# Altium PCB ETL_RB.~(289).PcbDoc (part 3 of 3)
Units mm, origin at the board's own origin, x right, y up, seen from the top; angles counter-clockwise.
Board outline 130.3 x 56.5 mm, 8 copper layers (Top Layer, plane 1, M1, plane 2, plane 3, M2, plane 4, Bottom Layer), stack 0.972 mm thick; 198 components, 185 nets, 1814 pads, 863 vias.
Unrouted connection lines stored in the file: 412.

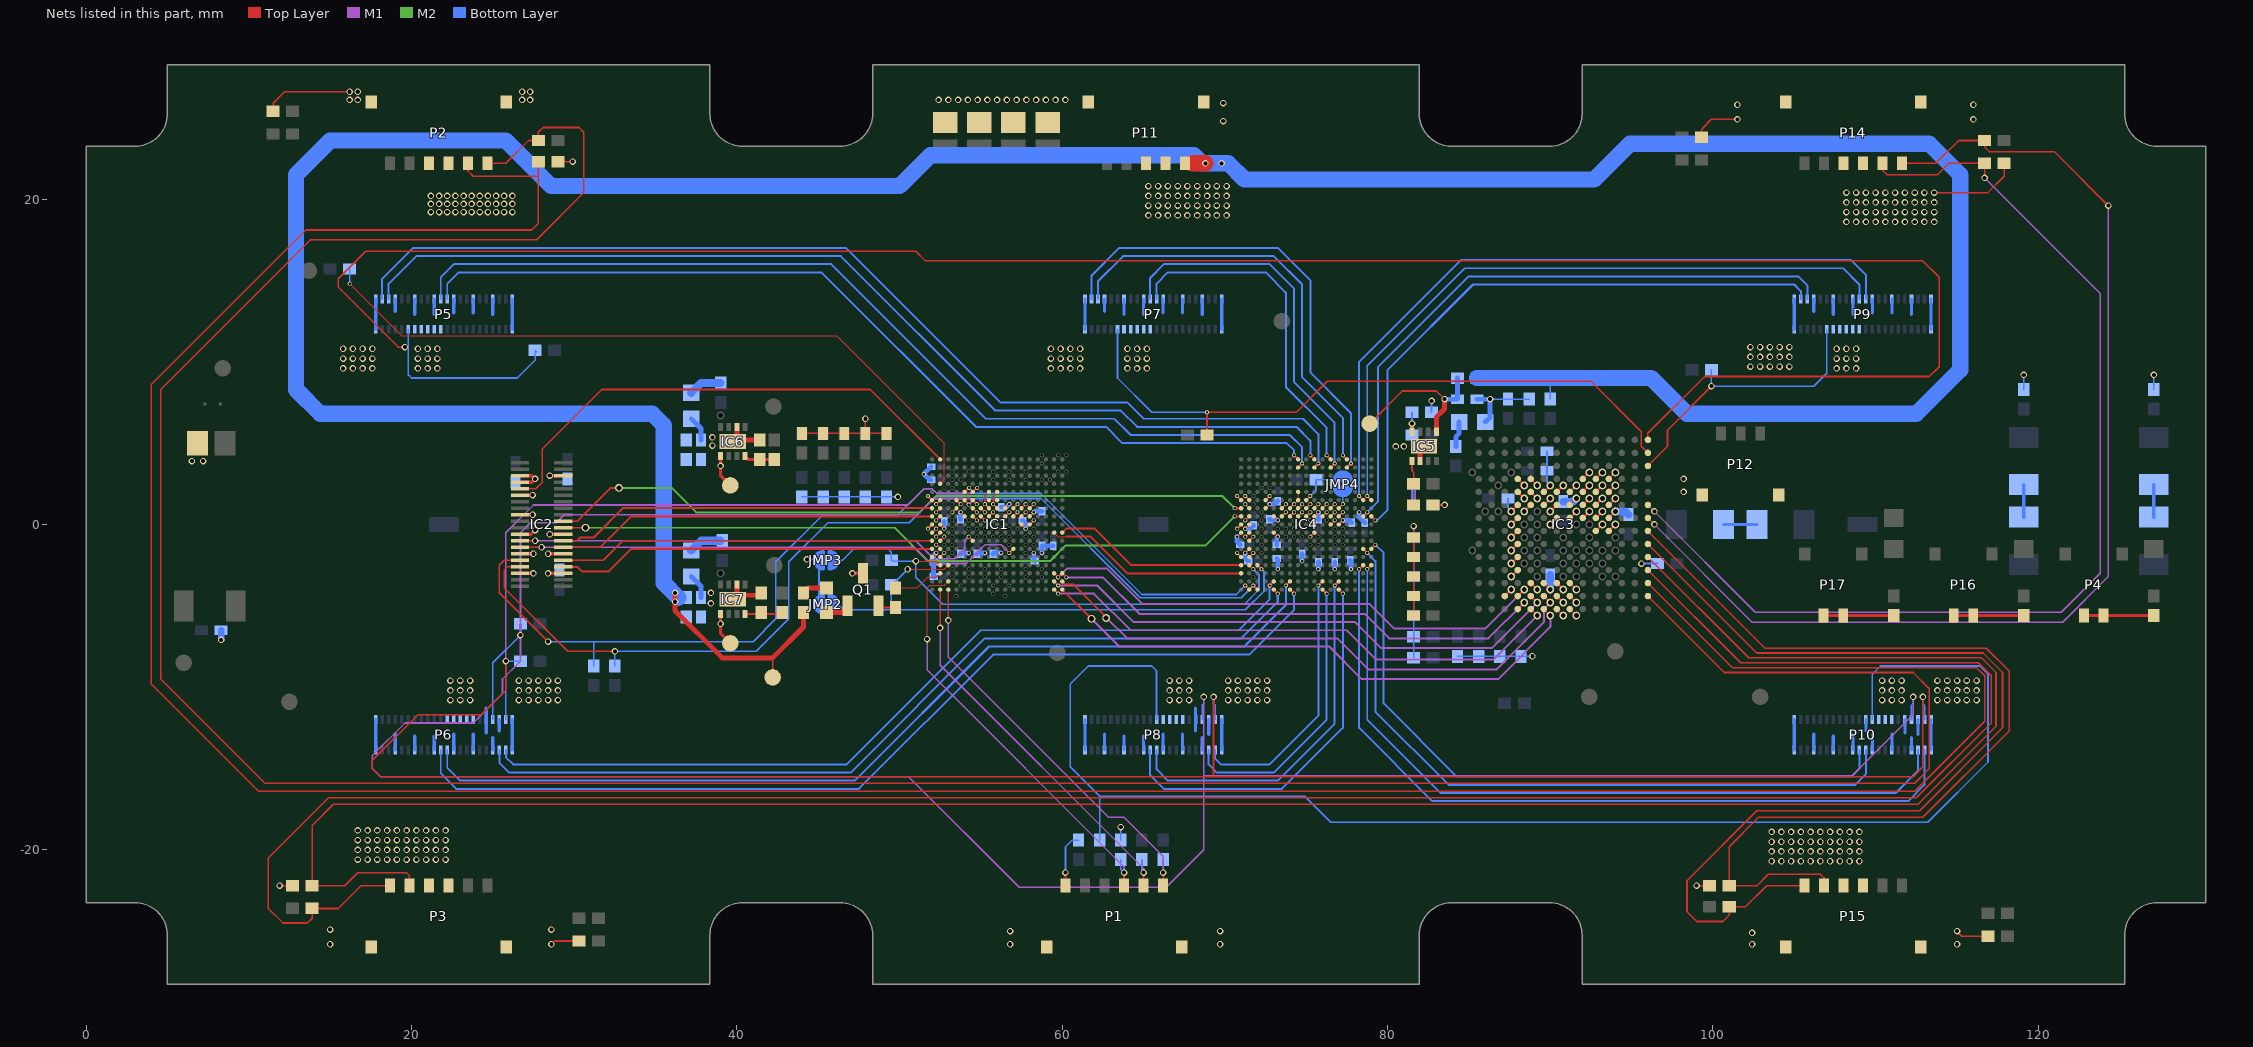
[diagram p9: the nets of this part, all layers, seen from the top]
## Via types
v1: diameter 0.4, hole 0.25, Top Layer to Bottom Layer, 863 vias

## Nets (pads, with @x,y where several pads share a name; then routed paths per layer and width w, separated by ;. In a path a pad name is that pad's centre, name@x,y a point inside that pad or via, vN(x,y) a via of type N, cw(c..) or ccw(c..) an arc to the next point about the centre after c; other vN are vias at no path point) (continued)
GND: C105.2 C106.2 C107.2 C108.2 C109.2 C111.2 C112.2 C113.2 C114.2 C115.2 C116.2 C117.2 C118.2 C119.2 C120.2 C121.2 C122.2 C123.2 C124.2 C125.2 C126.2 C127.2 C128.2 C129.2 C130.2 C131.2 C132.2 C133.2 C134.2 C135.2 C136.2 C138.2 C139.2 C140.2 C141.2 C142.2 C150.2 C151.2 C152.2 C153.2 C154.2 C155.2 C158.2 C159.2 C160.2 C162.2 C163.2 C164.2 C165.2 C166.2 C167.2 C168.2 C169.2 C201.1 C202.1 C203.1 C204.1 C205.1 C206.1 C207.1 C208.1 C209.1 C210.1 C211.1 C212.1 C213.1 C214.1 IC1.E8 IC1.E9 IC1.F1 IC1.F2 IC1.F4 IC1.F8 IC1.F9 IC1.G2 IC1.G4 IC1.G6 IC1.G7 IC1.G8 IC1.G9 IC1.G10 IC1.G11 IC1.G12 IC1.G13 IC1.H2 IC1.H5 IC1.H6 IC1.H7 IC1.H8 IC1.H9 IC1.H10 IC1.H11 IC1.H12 IC1.H13 IC1.J1 IC1.J2 IC1.J12 IC1.J13 IC1.K1 IC1.K2 IC1.L2 IC1.M2 IC1.N1 IC1.N2 IC2.5 IC2.6 IC2.11 IC2.12 IC2.17 IC2.18 IC2.24 IC2.30 IC2.34 IC2.35 IC2.36 IC3.D4 IC3.D5 IC3.D6 IC3.D7 IC3.D8 IC3.E4 IC3.E5 IC3.E6 IC3.E7 IC3.E8 IC3.F4 IC3.F5 IC3.F6 IC3.F7 IC3.G5 IC3.G6 IC3.G7 IC3.G12 IC3.G13 IC3.G14 IC3.H5 IC3.H6 IC3.H7 IC3.H12 IC3.H13 IC3.H14 IC3.J5 IC3.J6 IC3.J12 IC3.K4 IC3.K5 IC3.K6 IC3.K12 IC3.L4 IC3.L5 IC3.L6 IC3.L7 IC3.L8 IC3.L9 IC3.L10 IC3.L11 IC3.M13 IC4.E8 IC4.F1 IC4.F2 IC4.F4 IC4.F8 IC4.G2 IC4.G4 IC4.G6 IC4.G7 IC4.G8 IC4.G9 IC4.G10 IC4.G11 IC4.G12 IC4.G13 IC4.H2 IC4.H5 IC4.H6 IC4.H7 IC4.H8 IC4.H9 IC4.H10 IC4.H11 IC4.H12 IC4.H13 IC4.J1 IC4.J2 IC4.J10 IC4.J12 IC4.J13 IC4.K1 IC4.K2 IC4.K5 IC4.K10 IC4.L2 IC4.M2 IC4.N1 IC4.N2 IC5.6 IC5.9 IC6.6 IC6.9 IC7.6 IC7.9 JMP2.1 JMP3.1 JMP4.1 P1.6 P1.7 P1.8 P2.3 P2.4 P2.7 P2.8 P3.3 P3.4 P3.7 P3.8 P5.11 P5.12 P5.13 P5.14 P5.15 P5.23 P5.26 P5.29 P5.32 P5.35 P5.38 P5.41 P5.42 P5.43 P5.44 P6.11 P6.12 P6.13 P6.14 P6.15 P6.17 P6.19 P6.23 P6.26 P6.29 P6.32 P6.35 P6.38 P6.41 P6.42 P6.43 P6.44 P7.11 P7.12 P7.13 P7.14 P7.15 P7.23 P7.26 P7.29 P7.32 P7.35 P7.38 P7.41 P7.42 P7.43 P7.44 P8.12 P8.13 P8.14 P8.15 P8.17 P8.19 P8.23 P8.26 P8.29 P8.32 P8.35 P8.38 P8.41 P8.42 P8.43 P8.44 P9.11 P9.12 P9.13 P9.14 P9.15 P9.23 P9.26 P9.29 P9.32 P9.35 P9.38 P9.41 P9.42 P9.43 P9.44 P10.11 P10.13 P10.14 P10.15 P10.17 P10.19 P10.23 P10.26 P10.29 P10.32 P10.35 P10.38 P10.41 P10.42 P10.43 P10.44 P11.3 P11.4 P11.6 P11.7 P12.4 P12.5 P14.3 P14.4 P14.7 P14.8 P15.3 P15.4 P15.7 P15.8 pad.1@51.5,3.1 pad.1@51.75,1.75 pad.1@51.75,-0.25 pad.1@52.25,0.25 pad.1@52.25,0.75 pad.1@52.25,1.25 pad.1@52.25,-0.25 pad.1@52.25,-0.75 pad.1@52.25,-1.25 pad.1@52.25,-1.75 pad.1@52.75,-0.25 pad.1@52.75,-0.75 pad.1@52.75,-1.75 pad.1@53.25,0.75 pad.1@53.75,0.75 pad.1@53.75,1.25 pad.1@54.25,-1.75 pad.1@54.75,0.25 pad.1@54.75,0.75 pad.1@55.25,0.25 pad.1@55.25,0.75 pad.1@55.25,1.25 pad.1@55.25,-1.75 pad.1@55.75,0.25 pad.1@55.75,0.75 pad.1@55.75,1.25 pad.1@56.25,-1.75 pad.1@56.75,0.75 pad.1@56.75,1.25 pad.1@57.25,0.75 pad.1@57.25,1.25 pad.1@57.75,0.75 pad.1@57.75,1.25 pad.1@57.75,-0.25 pad.1@58.25,0.25 pad.1@58.25,0.75 pad.1@58.25,1.25 pad.1@58.25,-1.75 pad.1@58.75,-1.75 pad.1@70.75,1.75 pad.1@70.75,-0.25 pad.1@70.75,-0.75 pad.1@70.75,-1.75 pad.1@71.25,0.25 pad.1@71.25,1.25 pad.1@71.25,1.75 pad.1@71.25,-0.25 pad.1@71.25,-0.75 pad.1@71.25,-1.75 pad.1@71.75,-0.75 pad.1@71.75,-1.75 pad.1@72.75,1.25 pad.1@72.75,1.75 pad.1@73.25,0.25 pad.1@73.25,-0.75 pad.1@73.25,-2.75 pad.1@73.75,0.75 pad.1@73.75,1.25 pad.1@74.25,0.75 pad.1@74.25,1.25 pad.1@74.75,0.75 pad.1@74.75,1.25 pad.1@74.75,-2.25 pad.1@75.25,0.25 pad.1@75.25,0.75 pad.1@75.25,1.25 pad.1@75.25,-0.75 pad.1@75.75,0.75 pad.1@75.75,1.25 pad.1@75.75,-2.75 pad.1@76.25,0.75 pad.1@76.25,1.25 pad.1@76.75,0.25 pad.1@76.75,0.75 pad.1@76.75,1.25 pad.1@76.75,-2.75 pad.1@77.25,0.25 pad.1@77.25,0.75 pad.1@77.25,1.25 pad.1@77.75,-2.75 pad.1@78.25,0.75 pad.1@87.6,0 pad.1@87.6,0.8 pad.1@87.6,-0.8 pad.1@87.6,-1.6 pad.1@87.6,-2.4 pad.1@87.6,-3.2 pad.1@87.6,-4 pad.1@88.4,0.8 pad.1@88.4,1.6 pad.1@88.4,2.4 pad.1@89.2,1.6 pad.1@89.2,2.4 pad.1@89.2,-4 pad.1@90,0 pad.1@90,0.8 pad.1@90,1.6 pad.1@90,2.4 pad.1@90,-4 pad.1@90.8,2.4 pad.1@90.8,-4 pad.1@90.8,-4.8 pad.1@90.8,-5.6 pad.1@91.6,0.8 pad.1@91.6,1.6 pad.1@91.6,2.4 pad.1@91.6,-4 pad.1@91.6,-4.8 pad.1@91.6,-5.6 pad.1@92.4,0.8 pad.1@92.4,1.6 pad.1@92.4,2.4 pad.1@92.4,3.2 pad.1@93.2,0 pad.1@93.2,0.8 pad.1@93.2,1.6 pad.1@93.2,2.4 pad.1@93.2,3.2 pad.1@94,0 pad.1@94,0.8 pad.1@94,1.6 pad.1@94,2.4 pad.1@94,3.2 Q1.3 R112.2 R115.2 R118.1 R120.1 R122.1 R123.2 R126.2 R132.2 R134.1 R136.1 R143.1 R203.1 R205.1 R207.1 R209.1 R211.1 R213.1 R215.1 R217.1 R219.1 R221.1 R223.1 R225.1 R227.1 R229.1 R233.2 R234.2 R235.2 R236.2 | length 222
  Top Layer w0.076: pad.1@55.25,1.25 55.25,1.5 ; IC1.F8@55.5,1.5 55.25,1.5 ; IC1.E8@55.5,2 55.25,1.75 55.25,1.5 ; pad.1@55.75,1.25 55.75,1.5 ; IC1.F9@56,1.5 55.75,1.5 ; IC1.E9@56,2 55.75,1.75 55.75,1.5 ; pad.1@74.25,1.25 IC4.F8@74.5,1.5 IC4.E8@74.5,2
  Top Layer w0.102: R215.1@11.5,25.4 11.5,25.9 12.2,26.6 v1(16.2,26.6) ; v1(11.9,-22.2) R234.2@12.7,-22.2 ; v1(28.6,-25.8) 28.8,-25.6 R217.1@30.3,-25.6 ; R233.2@29,22.3 v1(29.9,22.3) ; C151.2@44,5.6 C150.2@45.3,5.6 C142.2@46.6,5.6 C109.2@47.9,5.6 ; v1(47.9,6.5) C109.2@47.9,5.6 ; C141.2@49.2,5.6 C109.2@47.9,5.6 ; P1.6@60.2,-22.2 v1(60.2,-21.4) ; C201.1@81.6,-5.6 C203.1@81.6,-4.4 C205.1@81.6,-3.2 C207.1@81.6,-2 C210.1@81.6,-0.8 v1(81.6,-0.1) ; R112.2@82.8,1.2 v1(83.5,1.2) ; v1(99,-22.2) R236.2@99.8,-22.2 ; R219.1@99.3,23.8 99.3,24.3 99.9,24.9 v1(101.5,24.9) ; v1(113.6,20.4) 116.9,20.4 117.9,21.4 R235.2@117.9,22.2 ; v1(115,-25) 115.3,-25.3 R221.1@116.9,-25.3
  Top Layer w0.13: pad.1@51.75,-0.25 IC1.J1@52,0 ; pad.1@51.75,1.75 IC1.F1@52,1.5 ; IC1.N1@52,-2 pad.1@52.25,-1.75 ; IC1.K1@52,-0.5 pad.1@52.25,-0.25 ; pad.1@52.25,-1.25 IC1.M2@52.5,-1.5 ; pad.1@52.25,-0.75 IC1.K2@52.5,-0.5 ; pad.1@52.25,0.25 IC1.H2@52.5,0.5 ; pad.1@52.25,0.75 IC1.G2@52.5,1 ; pad.1@52.25,1.25 IC1.F2@52.5,1.5 ; IC1.N2@52.5,-2 pad.1@52.75,-1.75 ; IC1.L2@52.5,-1 pad.1@52.75,-0.75 ; IC1.J2@52.5,0 pad.1@52.75,-0.25 ; pad.1@53.25,0.75 IC1.G4@53.5,1 ; IC1.F4@53.5,1.5 pad.1@53.75,1.25 ; pad.1@53.75,0.75 IC1.H5@54,0.5 ; IC1.H6@54.5,0.5 pad.1@54.75,0.25 ; IC1.G6@54.5,1 pad.1@54.75,0.75 ; IC1.H7@55,0.5 pad.1@55.25,0.25 ; IC1.G7@55,1 pad.1@55.25,0.75 ; pad.1@55.25,1.25 IC1.G8@55.5,1 ; IC1.H8@55.5,0.5 pad.1@55.75,0.75 ; pad.1@55.75,0.25 IC1.H9@56,0.5 ; pad.1@55.75,1.25 IC1.G9@56,1 ; IC1.H10@56.5,0.5 pad.1@56.75,0.75 ; IC1.G10@56.5,1 pad.1@56.75,1.25 ; IC1.H11@57,0.5 pad.1@57.25,0.75 ; IC1.G11@57,1 pad.1@57.25,1.25 ; IC1.J12@57.5,0 pad.1@57.75,-0.25 ; IC1.H12@57.5,0.5 pad.1@57.75,0.75 ; IC1.G12@57.5,1 pad.1@57.75,1.25 ; IC1.J13@58,0 pad.1@58.25,0.25 ; IC1.H13@58,0.5 pad.1@58.25,0.75 ; IC1.G13@58,1 pad.1@58.25,1.25 ; pad.1@70.75,-1.75 IC4.N1@71,-2 ; pad.1@70.75,-0.75 IC4.K1@71,-0.5 ; pad.1@70.75,-0.25 IC4.J1@71,0 ; pad.1@70.75,1.75 IC4.F1@71,1.5 ; pad.1@71.25,-1.75 IC4.M2@71.5,-1.5 ; pad.1@71.25,-0.75 IC4.K2@71.5,-0.5 ; pad.1@71.25,-0.25 IC4.J2@71.5,0 ; pad.1@71.25,0.25 IC4.H2@71.5,0.5 ; pad.1@71.25,1.25 IC4.G2@71.5,1 ; pad.1@71.25,1.75 IC4.F2@71.5,1.5 ; IC4.N2@71.5,-2 pad.1@71.75,-1.75 ; IC4.L2@71.5,-1 pad.1@71.75,-0.75 ; IC4.G4@72.5,1 pad.1@72.75,1.25 ; IC4.F4@72.5,1.5 pad.1@72.75,1.75 ; IC4.K5@73,-0.5 pad.1@73.25,-0.75 ; IC4.H5@73,0.5 pad.1@73.25,0.25 ; IC4.H6@73.5,0.5 pad.1@73.75,0.75 ; IC4.G6@73.5,1 pad.1@73.75,1.25 ; IC4.H7@74,0.5 pad.1@74.25,0.75 ; IC4.G7@74,1 pad.1@74.25,1.25 ; IC4.H8@74.5,0.5 pad.1@74.75,0.75 ; IC4.G8@74.5,1 pad.1@74.75,1.25 ; IC4.H9@75,0.5 pad.1@75.25,0.75 ; IC4.G9@75,1 pad.1@75.25,1.25 ; pad.1@75.25,-0.75 IC4.K10@75.5,-0.5 ; pad.1@75.25,0.25 IC4.J10@75.5,0 ; IC4.H10@75.5,0.5 pad.1@75.75,0.75 ; IC4.G10@75.5,1 pad.1@75.75,1.25 ; IC4.H11@76,0.5 pad.1@76.25,0.75 ; IC4.G11@76,1 pad.1@76.25,1.25 ; IC4.J12@76.5,0 pad.1@76.75,0.25 ; IC4.H12@76.5,0.5 pad.1@76.75,0.75 ; IC4.G12@76.5,1 pad.1@76.75,1.25 ; IC4.J13@77,0 pad.1@77.25,0.25 ; IC4.H13@77,0.5 pad.1@77.25,0.75 ; IC4.G13@77,1 pad.1@77.25,1.25 ; IC3.M13@87.2,-4.4 pad.1@87.6,-4 ; pad.1@87.6,-3.2 IC3.L11@88,-2.8 ; pad.1@87.6,-2.4 IC3.L10@88,-2 ; pad.1@87.6,-1.6 IC3.L9@88,-1.2 ; pad.1@87.6,-0.8 IC3.L8@88,-0.4 ; pad.1@87.6,0 IC3.L7@88,0.4 ; pad.1@87.6,0.8 IC3.L6@88,1.2 ; IC3.L5@88,2 pad.1@88.4,1.6 ; IC3.L4@88,2.8 pad.1@88.4,2.4 ; pad.1@88.4,0.8 IC3.K6@88.8,1.2 ; IC3.K12@88.8,-3.6 pad.1@89.2,-4 ; IC3.K5@88.8,2 pad.1@89.2,1.6 ; IC3.K4@88.8,2.8 pad.1@89.2,2.4 ; IC3.J12@89.6,-3.6 pad.1@90,-4 ; IC3.J6@89.6,1.2 pad.1@90,1.6 ; IC3.J5@89.6,2 pad.1@90,2.4 ; pad.1@90,0 IC3.H7@90.4,0.4 ; pad.1@90,0.8 IC3.H6@90.4,1.2 ; IC3.H14@90.4,-5.2 pad.1@90.8,-5.6 ; IC3.H13@90.4,-4.4 pad.1@90.8,-4.8 ; IC3.H12@90.4,-3.6 pad.1@90.8,-4 ; IC3.H5@90.4,2 pad.1@90.8,2.4 ; IC3.G14@91.2,-5.2 pad.1@91.6,-5.6 ; IC3.G13@91.2,-4.4 pad.1@91.6,-4.8 ; IC3.G12@91.2,-3.6 pad.1@91.6,-4 ; IC3.G7@91.2,0.4 pad.1@91.6,0.8 ; IC3.G6@91.2,1.2 pad.1@91.6,1.6 ; IC3.G5@91.2,2 pad.1@91.6,2.4 ; IC3.F7@92,0.4 pad.1@92.4,0.8 ; IC3.F6@92,1.2 pad.1@92.4,1.6 ; IC3.F5@92,2 pad.1@92.4,2.4 ; IC3.F4@92,2.8 pad.1@92.4,3.2 ; IC3.E8@92.8,-0.4 pad.1@93.2,0 ; IC3.E7@92.8,0.4 pad.1@93.2,0.8 ; IC3.E6@92.8,1.2 pad.1@93.2,1.6 ; IC3.E5@92.8,2 pad.1@93.2,2.4 ; IC3.E4@92.8,2.8 pad.1@93.2,3.2 ; IC3.D8@93.6,-0.4 pad.1@94,0 ; IC3.D7@93.6,0.4 pad.1@94,0.8 ; IC3.D6@93.6,1.2 pad.1@94,1.6 ; IC3.D5@93.6,2 pad.1@94,2.4 ; IC3.D4@93.6,2.8 pad.1@94,3.2
  Top Layer w0.2: IC2.6@26.67,-3 v1(27.5,-3) ; IC2.12@26.67,-1.8 v1(27.5,-1.8) ; IC2.18@26.67,-0.6 27.35,-0.6 v1(27.6,-0.35) ; IC2.24@26.67,0.6 v1(27.45,0.6) ; IC2.30@26.67,1.8 v1(27.45,1.8) ; IC2.34@26.67,2.6 27.4,2.6 v1(27.6,2.8) 27.4,3 IC2.36@26.67,3 ; v1(28.4,-3) IC2.5@29.33,-3 ; v1(28.4,-1.8) IC2.11@29.33,-1.8 ; v1(28.5,-0.6) IC2.17@29.33,-0.6 ; v1(28.5,3) IC2.35@29.33,3 ; v1(47.1,-3) Q1.3@47.75,-3
  Top Layer w0.3: IC7.9@39.75,-4.6 IC7.9@40,-4.35 ; IC7.6@40,-3.7 IC7.9@40,-4.35 ; IC6.6@40,6 40,5.35 39.875,5.225 39.9,5.2 R115.2@41.4,5.2 ; R123.2@41.5,-4.2 41.55,-4.2 41.4,-4.35 IC7.9@40,-4.35 ; IC5.6@82,3.9 82,4.55 IC5.9@82.25,4.8
  Bottom Layer w0.102: R122.1@44,1.7 R120.1@45.3,1.7 R136.1@46.6,1.7 R118.1@47.9,1.7 R134.1@49.2,1.7 v1(49.9,1.7) ; v1(44.3,-2.15) 44.803,-2.15 44.95,-2.15 JMP3.1@45,-2.2 ; 45.05,-4.467 45.05,-2.633 ; v1(60.2,-21.4) 60.2,-19.8 60.6,-19.4 R132.2@61,-19.4 ; R143.1@63.6,-19.4 v1(63.6,-18.6) ; pad.1@77.25,1.25 77.25,1.8 JMP4.1@77.25,2 ; R203.1@81.6,-8.2 R205.1@81.6,-6.9 C202.1@81.6,-5.6 C204.1@81.6,-4.4 C206.1@81.6,-3.2 C208.1@81.6,-2 C209.1@81.6,-0.8 81.6,-0.2 v1(81.6,-0.1) ; R126.2@82.7,6.9 v1(82.7,7.6) ; C155.2@82.8,1.2 v1(83.5,1.2) ; R207.1@84.3,-8.1 R209.1@85.6,-8.1 R211.1@86.9,-8.1 R213.1@88.2,-8.1 v1(88.9,-8.1) ; v1(86.3,7.7) C214.1@87.4,7.7 R229.1@88.7,7.7 ; C211.1@87.4,1.6 87.4,1 pad.1@87.6,0.8 ; C213.1@89.8,4.5 C212.1@89.8,3.3 89.8,2.6 pad.1@90,2.4 ; v1(95.6,-2.4) R227.1@96.6,-2.4 ; R225.1@119.1,8.3 v1(119.1,9.2) ; R223.1@127.1,8.3 v1(127.1,9.2)
  Bottom Layer w0.2: P6.44@17.8,-13.85 P6.41@17.8,-12 ; P5.42@17.8,12 P5.43@17.8,13.85 ; P6.38@19,-13.85 19,-12.9 ; 19,13.1 P5.23@19,13.85 ; P6.35@20.2,-13.85 20.2,-13 ; 20.2,12.9 P5.26@20.2,13.85 ; P6.32@21.4,-13.85 21.4,-13 ; 21.4,12.9 P5.29@21.4,13.85 ; P6.29@22.6,-13.85 22.6,-12.9 ; 22.6,13 P5.32@22.6,13.85 ; P6.26@23.8,-13.85 23.8,-12.9 ; 23.8,13 P5.35@23.8,13.85 ; 24.6,-12.8 P6.17@24.6,-12 24.6,-11.3 ; P6.23@25,-13.85 25,-13.1 ; 25,12.9 P5.38@25,13.85 ; 25.4,-12.7 P6.19@25.4,-12 ; P6.43@26.2,-13.85 P6.42@26.2,-12 ; P5.41@26.2,12 P5.44@26.2,13.85 ; P8.44@61.4,-13.85 P8.41@61.4,-12 ; P7.42@61.4,12 P7.43@61.4,13.85 ; P8.38@62.6,-13.85 62.6,-12.9 ; 62.6,13.1 P7.23@62.6,13.85 ; P8.35@63.8,-13.85 63.8,-13 ; 63.8,12.9 P7.26@63.8,13.85 ; P8.32@65,-13.85 65,-13 ; 65,12.9 P7.29@65,13.85 ; P8.29@66.2,-13.85 66.2,-12.9 ; 66.2,13 P7.32@66.2,13.85 ; P8.26@67.4,-13.85 67.4,-12.9 ; 67.4,13 P7.35@67.4,13.85 ; 68.2,-12.7 P8.17@68.2,-12 68.2,-11.3 ; P8.23@68.6,-13.85 68.6,-13.1 ; 68.6,12.9 P7.38@68.6,13.85 ; 69,-12.9 P8.19@69,-12 ; P8.43@69.8,-13.85 P8.42@69.8,-12 ; P7.41@69.8,12 P7.44@69.8,13.85 ; P10.44@105,-13.85 P10.41@105,-12 ; P9.42@105,12 P9.43@105,13.85 ; P10.38@106.2,-13.85 106.2,-12.9 ; 106.2,13.1 P9.23@106.2,13.85 ; P10.35@107.4,-13.85 107.4,-13 ; 107.4,12.9 P9.26@107.4,13.85 ; P10.32@108.6,-13.85 108.6,-13 ; 108.6,12.9 P9.29@108.6,13.85 ; 109.4,-12.7 P10.11@109.4,-12 ; P10.29@109.8,-13.85 109.8,-12.9 ; 109.8,13 P9.32@109.8,13.85 ; P10.26@111,-13.85 111,-12.9 ; 111,13 P9.35@111,13.85 ; 111.8,-12.8 P10.17@111.8,-12 ; P10.23@112.2,-13.85 112.2,-13.1 ; 112.2,12.9 P9.38@112.2,13.85 ; 112.6,-12.9 P10.19@112.6,-12 ; P10.43@113.4,-13.85 P10.42@113.4,-12 ; P9.41@113.4,12 P9.44@113.4,13.85
  Bottom Layer w0.3: C169.2@37.2,-3.2 37.8,-3.8 C152.2@37.8,-4.5 ; C108.2@37.2,6.5 37.8,5.9 C106.2@37.8,5.2 ; C119.2@51.94,2.75 51.85,2.75 pad.1@51.5,3.1 51.5,3.11 C118.2@51.94,3.55 ; C121.2@52.09,-3.2 52.174,-3.2 52.09,-3.116 C125.2@52.09,-2.3 52.09,-1.91 pad.1@52.25,-1.75 ; pad.1@52.75,-0.25 C116.2@52.75,0.19 ; C117.2@53.75,-1.81 53.81,-1.75 pad.1@54.25,-1.75 ; C126.2@53.75,0.31 pad.1@53.75,0.75 ; C114.2@54.75,-1.81 54.81,-1.75 pad.1@55.25,-1.75 ; C122.2@55.75,-1.81 55.81,-1.75 pad.1@56.25,-1.75 ; C120.2@56.25,1.06 56.56,1.06 pad.1@56.75,1.25 ; C136.2@57.56,0.25 57.75,0.06 pad.1@57.75,-0.25 ; pad.1@58.25,-1.75 58.25,-2.19 C123.2@58.31,-2.25 ; pad.1@58.25,0.75 58.31,0.81 C124.2@58.75,0.81 ; pad.1@58.75,-1.75 C115.2@58.75,-1.31 C113.2@59.45,-1.31 ; pad.1@70.75,-0.75 70.75,-1.06 C130.2@70.94,-1.25 ; pad.1@71.25,-1.75 71.25,-2.06 C132.2@71.44,-2.25 ; pad.1@71.25,-0.25 71.56,-0.25 C164.2@71.75,-0.06 ; C163.2@72.75,0.31 73.19,0.31 pad.1@73.25,0.25 ; pad.1@72.75,1.25 73.06,1.25 C167.2@73.25,1.44 ; C133.2@73.19,-2.1 73.25,-2.16 pad.1@73.25,-2.75 ; C168.2@73.19,-1.25 73.19,-0.81 pad.1@73.25,-0.75 ; pad.1@74.75,-2.25 C128.2@74.75,-1.81 ; pad.1@75.75,-2.75 C134.2@75.75,-2.31 ; C131.2@75.75,0.31 pad.1@75.75,0.75 ; pad.1@76.75,-2.75 C165.2@76.75,-2.31 ; pad.1@77.25,0.25 77.66,0.25 C166.2@77.8,0.11 ; C135.2@77.7,-2.21 77.75,-2.26 pad.1@77.75,-2.75 ; pad.1@78.25,0.75 78.25,0.46 C129.2@78.6,0.11 ; C105.2@85.5,7.7 v1(86.3,7.7) 86.3,6.6 C107.2@86,6.3
  Bottom Layer w0.4: v1(8.3,-7.1) C158.2@8.3,-6.5
  Bottom Layer w0.48: pad.1@90,-4 C138.2@90,-3.1 ; C140.2@90.8,1.4 91.4,1.4 pad.1@91.6,1.6 ; pad.1@94,0.8 94.6,0.8 C139.2@94.8,0.6
  other v1: 15,-25.8 56.8,-25.8 69.7,-25.8 102.4,-25.8 115,-25.8 102.4,-25.1 56.8,-25 69.7,-25 15,-24.9 28.6,-24.9 103.6,-20.7 104.2,-20.7 104.8,-20.7 105.4,-20.7 106,-20.7 106.6,-20.7 107.2,-20.7 107.8,-20.7 108.4,-20.7 109,-20.7 16.7,-20.6 17.3,-20.6 17.9,-20.6 18.5,-20.6 19.1,-20.6 19.7,-20.6 20.3,-20.6 20.9,-20.6 21.5,-20.6 22.1,-20.6 103.6,-20.1 104.2,-20.1 104.8,-20.1 105.4,-20.1 106,-20.1 106.6,-20.1 107.2,-20.1 107.8,-20.1 108.4,-20.1 109,-20.1 16.7,-20 17.3,-20 17.9,-20 18.5,-20 19.1,-20 19.7,-20 20.3,-20 20.9,-20 21.5,-20 22.1,-20 103.6,-19.5 104.2,-19.5 104.8,-19.5 105.4,-19.5 106,-19.5 106.6,-19.5 107.2,-19.5 107.8,-19.5 108.4,-19.5 109,-19.5 16.7,-19.4 17.3,-19.4 17.9,-19.4 18.5,-19.4 19.1,-19.4 19.7,-19.4 20.3,-19.4 20.9,-19.4 21.5,-19.4 22.1,-19.4 103.6,-18.9 104.2,-18.9 104.8,-18.9 105.4,-18.9 106,-18.9 106.6,-18.9 107.2,-18.9 107.8,-18.9 108.4,-18.9 109,-18.9 16.7,-18.8 17.3,-18.8 17.9,-18.8 18.5,-18.8 19.1,-18.8 19.7,-18.8 20.3,-18.8 20.9,-18.8 21.5,-18.8 22.1,-18.8 22.4,-10.8 23,-10.8 23.6,-10.8 26.6,-10.8 27.2,-10.8 27.8,-10.8 28.4,-10.8 29,-10.8 66.6,-10.8 67.2,-10.8 67.8,-10.8 70.2,-10.8 70.8,-10.8 71.4,-10.8 72,-10.8 72.6,-10.8 110.4,-10.8 111,-10.8 111.6,-10.8 113.8,-10.8 114.4,-10.8 115,-10.8 115.6,-10.8 116.2,-10.8 22.4,-10.2 23,-10.2 23.6,-10.2 26.6,-10.2 27.2,-10.2 27.8,-10.2 28.4,-10.2 29,-10.2 66.6,-10.2 67.2,-10.2 67.8,-10.2 70.2,-10.2 70.8,-10.2 71.4,-10.2 72,-10.2 72.6,-10.2 110.4,-10.2 111,-10.2 111.6,-10.2 113.8,-10.2 114.4,-10.2 115,-10.2 115.6,-10.2 116.2,-10.2 22.4,-9.6 23,-9.6 23.6,-9.6 26.6,-9.6 27.2,-9.6 27.8,-9.6 28.4,-9.6 29,-9.6 66.6,-9.6 67.2,-9.6 67.8,-9.6 70.2,-9.6 70.8,-9.6 71.4,-9.6 72,-9.6 72.6,-9.6 110.4,-9.6 111,-9.6 111.6,-9.6 113.8,-9.6 114.4,-9.6 115,-9.6 115.6,-9.6 116.2,-9.6 38.4,-4.85 38.4,-4.2 98.2,2 98.2,2.8 6.5,3.9 7.2,3.9 80.5,4.8 81,4.8 38.5,4.85 38.5,5.35 15.8,9.6 16.4,9.6 17,9.6 17.6,9.6 20.4,9.6 21,9.6 21.6,9.6 59.3,9.6 59.9,9.6 60.5,9.6 61.1,9.6 64,9.6 64.6,9.6 65.2,9.6 107.6,9.6 108.2,9.6 108.8,9.6 102.3,9.7 102.9,9.7 103.5,9.7 104.1,9.7 104.7,9.7 15.8,10.2 16.4,10.2 17,10.2 17.6,10.2 20.4,10.2 21,10.2 21.6,10.2 59.3,10.2 59.9,10.2 60.5,10.2 61.1,10.2 64,10.2 64.6,10.2 65.2,10.2 107.6,10.2 108.2,10.2 108.8,10.2 102.3,10.3 102.9,10.3 103.5,10.3 104.1,10.3 104.7,10.3 15.8,10.8 16.4,10.8 17,10.8 17.6,10.8 20.4,10.8 21,10.8 21.6,10.8 59.3,10.8 59.9,10.8 60.5,10.8 61.1,10.8 64,10.8 64.6,10.8 65.2,10.8 107.6,10.8 108.2,10.8 108.8,10.8 102.3,10.9 102.9,10.9 103.5,10.9 104.1,10.9 104.7,10.9 108.2,18.6 108.8,18.6 109.4,18.6 110,18.6 110.6,18.6 111.2,18.6 111.8,18.6 112.4,18.6 113,18.6 113.6,18.6 65.3,19 65.9,19 66.5,19 67.1,19 67.7,19 68.3,19 68.9,19 69.5,19 70.1,19 21.2,19.2 21.7,19.2 22.2,19.2 22.7,19.2 23.2,19.2 23.7,19.2 24.2,19.2 24.7,19.2 25.2,19.2 25.7,19.2 26.2,19.2 108.2,19.2 108.8,19.2 109.4,19.2 110,19.2 110.6,19.2 111.2,19.2 111.8,19.2 112.4,19.2 113,19.2 113.6,19.2 65.3,19.6 65.9,19.6 66.5,19.6 67.1,19.6 67.7,19.6 68.3,19.6 68.9,19.6 69.5,19.6 70.1,19.6 21.2,19.7 21.7,19.7 22.2,19.7 22.7,19.7 23.2,19.7 23.7,19.7 24.2,19.7 24.7,19.7 25.2,19.7 25.7,19.7 26.2,19.7 108.2,19.8 108.8,19.8 109.4,19.8 110,19.8 110.6,19.8 111.2,19.8 111.8,19.8 112.4,19.8 113,19.8 113.6,19.8 21.2,20.2 21.7,20.2 22.2,20.2 22.7,20.2 23.2,20.2 23.7,20.2 24.2,20.2 24.7,20.2 25.2,20.2 25.7,20.2 26.2,20.2 65.3,20.2 65.9,20.2 66.5,20.2 67.1,20.2 67.7,20.2 68.3,20.2 68.9,20.2 69.5,20.2 70.1,20.2 108.2,20.4 108.8,20.4 109.4,20.4 110,20.4 110.6,20.4 111.2,20.4 111.8,20.4 112.4,20.4 113,20.4 65.3,20.8 65.9,20.8 66.5,20.8 67.1,20.8 67.7,20.8 68.3,20.8 68.9,20.8 69.5,20.8 70.1,20.8 69.9,24.8 116,24.9 101.5,25.8 116,25.8 69.9,25.9 16.2,26.1 16.7,26.1 26.8,26.1 27.3,26.1 52.4,26.1 53,26.1 53.6,26.1 54.2,26.1 54.8,26.1 55.4,26.1 56,26.1 56.6,26.1 57.2,26.1 57.8,26.1 58.4,26.1 59,26.1 59.6,26.1 60.2,26.1 16.7,26.6 26.8,26.6 27.3,26.6
I_1V5: C105.1 IC5.1 R129.2 TP15.1 | length 9.9
  Top Layer w0.102: TP15.1@78.9,6.2 80.9,8.2 83,8.2 v1(83.5,7.7)
  Top Layer w0.3: IC5.1@83,5.7 83,6.6 83.5,7.1 v1(83.5,7.7)
  Bottom Layer w0.3: v1(83.5,7.7) C105.1@84.3,7.7 R129.2@84.3,9
I_2V5RX: C152.1 IC7.1 R131.2 TP16.1 | length 2
  Top Layer w0.2: IC7.1@39,-5.5 v1(39,-6.1) 39,-6.7 TP16.1@39.6,-7.3
I_2V5TX: C106.1 IC6.1 R130.2 TP17.1 | length 2
  Top Layer w0.2: IC6.1@39,4.2 v1(39,3.6) 39,3 TP17.1@39.6,2.4
IC1_SCL: IC1.U2 P1.2 R110.1 | length 24.2
  Top Layer w0.102: v1(52.5,-6.35) IC1.U2@52.5,-4 ; P1.2@65,-22.2 v1(65,-21.4)
  M1 w0.102: v1(52.5,-6.35) 52.5,-8.65 65,-21.15 v1(65,-21.4)
  Bottom Layer w0.102: R110.1@64.9,-20.6 64.9,-21.3 v1(65,-21.4)
IC1_SDA: IC1.U3 P1.1 R109.1 | length 25
  Top Layer w0.102: v1(53,-5.9) 53,-4.9 IC1.U3@53,-4 ; P1.1@66.2,-22.2 v1(66.2,-21.4)
  M1 w0.102: v1(53,-5.9) 53,-6.4 53,-8.15 62.85,-18 63.8,-18 66.2,-20.4 v1(66.2,-21.4)
  Bottom Layer w0.102: v1(66.2,-21.4) R109.1@66.2,-20.6
LD_DIS: IC1.L6 IC2.16 pad.1@54.25,-0.75 | length 29.2
  Top Layer w0.102: IC2.16@26.67,-1 v1(27.6,-1)
  Top Layer w0.13: pad.1@54.25,-0.75 IC1.L6@54.5,-1
  M1 w0.102: v1(27.6,-1) 51,-1 52.1,-2.1 53.4,-2.1 54,-1.5 54,-1 pad.1@54.25,-0.75
LD_RSTN: IC1.M11 IC2.14 pad.1@56.75,-1.75 | length 31.5
  Top Layer w0.102: IC2.14@26.67,-1.4 v1(28,-1.4)
  Top Layer w0.13: pad.1@56.75,-1.75 IC1.M11@57,-1.5
  M1 w0.102: v1(28,-1.4) 50.9,-1.4 51.9,-2.4 54.1,-2.4 55.25,-1.25 56.25,-1.25 pad.1@56.75,-1.75
LV_RB: P11.5 R129.1 R130.1 R131.1 R142.1 R228.2 TP5.1 | length 214
  Top Layer w0.102: TP5.1@42.2,-9.4 42.2,-8.2
  Top Layer w0.3: v1(36.2,-4.2) v1(36.2,-4.75) 36.2,-5.3 39.1,-8.2 42.2,-8.2 44.1,-6.3 R142.1@44.1,-5.4
  Top Layer w1: 68,22.2 v1(68.8,22.2)
  Bottom Layer w0.102: R228.2@90,7.7 90,9
  Bottom Layer w1: 36.4,-4.5 35.5,-3.6 35.5,6.1 34.8,6.8 14.4,6.8 12.9,8.3 12.9,21.5 15,23.6 25.8,23.6 28.6,20.8 50,20.8 51.9,22.7 68.1,22.7 68.6,22.2 v1(68.8,22.2) v1(69.8,22.2) 70.2,22.2 71.2,21.2 92.7,21.2 94.9,23.4 113.3,23.4 115.2,21.5 115.2,9.5 112.5,6.8 98.4,6.8 96.2,9 90,9 R129.1@85.5,9
M1SCL: IC1.E6 P6.20 P8.20 P10.20 pad.1@54.775,2.25 R103.1 | length 163.3
  Top Layer w0.102: v1(25.8,-8.4) 25.8,-10.2 24.3,-11.7 20.4,-11.7 17.6,-14.5 17.6,-15 18.1,-15.5 69.3,-15.5 ; v1(69.3,-10.6) 69.3,-15.5 ; v1(112.9,-10.6) 112.9,-14.9 112.3,-15.5 69.3,-15.5
  Top Layer w0.13: IC1.E6@54.5,2 54.75,2.25 pad.1@54.775,2.25
  M1 w0.102: v1(25.8,-8.4) 25.8,-0.5 27.5,1.2 50.5,1.2 51.5,2.2 52,2.2 52.3,1.9 54.425,1.9 pad.1@54.775,2.25
  Bottom Layer w0.1: v1(69.3,-10.6) 69.3,-11 69.4,-11.1 P8.20@69.4,-12 ; v1(112.9,-10.6) 112.9,-11 113,-11.1 P10.20@113,-12
  Bottom Layer w0.102: P6.20@25.8,-12 v1(25.8,-8.4) R103.1@26.7,-8.4
M1SDA: IC1.F6 P6.18 P8.18 P10.18 pad.1@54.75,1.25 R104.1 | length 170.4
  Top Layer w0.13: IC1.F6@54.5,1.5 pad.1@54.75,1.25
  M1 w0.1: 66.4,-22.3 68.7,-20 ; 108.55,-15.45 112.3,-11.7 v1(112.3,-10.6)
  M1 w0.102: pad.1@54.75,1.25 54.4,1.6 52.1,1.6 51.1,0.6 29.4,0.6 28.9,0.1 27.3,0.1 26.7,-0.5 v1(26.7,-6.8) 26.7,-8.4 25.6,-9.5 25.6,-10.4 23.8,-12.2 19.6,-12.2 17.6,-14.2 17.6,-15 18.1,-15.5 50.55,-15.5 57.35,-22.3 66.4,-22.3 ; 68.7,-20 68.7,-15.45 ; v1(68.7,-10.6) 68.7,-15.45 ; 108.55,-15.45 68.7,-15.45
  Bottom Layer w0.1: P8.18@68.6,-12 68.6,-11.1 68.7,-11 v1(68.7,-10.6) ; P10.18@112.2,-12 112.2,-11.1 112.3,-11 v1(112.3,-10.6)
  Bottom Layer w0.102: P6.18@25,-12 25,-8.5 v1(26.7,-6.8) R104.1@26.7,-6.1
M2SCL: IC1.E5 IC2.10 IC4.U2 pad.1@54.275,2.25 pad.1@71.25,-3.75 R105.1 | length 61.6
  Top Layer w0.102: IC2.10@26.67,-2.2 25.7,-2.2 25.4,-2.5 25.4,-4.2 v1(28.4,-7.2)
  Top Layer w0.13: IC1.E5@54,2 54.25,2.25 pad.1@54.275,2.25 ; pad.1@71.25,-3.75 IC4.U2@71.5,-4
  Bottom Layer w0.102: v1(28.4,-7.2) 31.2,-7.2 ; R105.1@31.2,-8.7 31.2,-7.2 ; pad.1@71.25,-3.75 70.7,-4.3 64.9,-4.3 58.7,1.9 54.625,1.9 pad.1@54.275,2.25 53.925,1.9 52.3,1.9 52,2.2 51.5,2.2 49.9,0.6 45.3,0.6 42.4,-2.3 42.4,-5.8 41,-7.2 31.2,-7.2
M2SDA: IC1.F5 IC2.8 IC4.U3 pad.1@54.251,1.226 pad.1@71.75,-3.75 R106.1 | length 60.5
  Top Layer w0.102: IC2.8@26.67,-2.6 25.9,-2.6 25.7,-2.8 25.7,-3.9 29.6,-7.8 v1(32.5,-7.8)
  Top Layer w0.13: IC1.F5@54,1.5 54.251,1.249 pad.1@54.251,1.226 ; pad.1@71.75,-3.75 IC4.U3@72,-4
  Bottom Layer w0.102: R106.1@32.5,-8.7 v1(32.5,-7.8) 41.2,-7.8 43.2,-5.8 43.2,-2.3 45.6,0.1 50.6,0.1 52.1,1.6 53.877,1.6 pad.1@54.251,1.226 54.625,1.6 58.7,1.6 64.8,-4.5 71,-4.5 pad.1@71.75,-3.75
NetC107_1: C107.1 R111.2 | length 1.6
  Bottom Layer w0.3: R111.2@84.2,4.8 84.2,5.4 84.4,5.6 C107.1@84.4,6.3
NetC108_1: C108.1 R114.1 | length 2
  Bottom Layer w0.5: C108.1@37.2,8.1 37.8,8.7 R114.1@39,8.7
NetC155_1: C155.1 R128.2 | length 1.3
  Bottom Layer w0.3: C155.1@81.6,1.2 R128.2@81.6,2.5
NetC169_1: C169.1 R125.1 | length 2
  Bottom Layer w0.5: C169.1@37.2,-1.6 37.8,-1 R125.1@39,-1
NetD1_1: D1.1 R142.2 | length 1.8
  Top Layer w0.127: D1.1@45.3,-4.1 D1.1@45.5,-3.9
  Top Layer w0.3: R142.2@44.1,-4.2 44.4,-3.9 D1.1@45.5,-3.9
NetD1_2: D1.2 Q1.1 | length 1.5
  Top Layer w0.3: D1.2@45.5,-5.4 46.4,-5.4 Q1.1@46.8,-5
NetIC1_A2: IC1.A2 IC2.32 | length 31.3
  Top Layer w0.102: IC2.32@26.67,2.2 27.65,2.2 28.05,2.6 28.05,4.65 31.7,8.3 48.2,8.3 IC1.A2@52.5,4
NetIC1_G1: IC1.G1 IC2.15 | length 23.5
  Top Layer w0.12: IC2.15@29.33,-1 30.165,-1 30.365,-0.8 31.2,-0.8 33,1 IC1.G1@52,1
NetIC1_H1: IC1.H1 IC2.13 | length 23.5
  Top Layer w0.12: IC2.13@29.33,-1.4 31.6,-1.4 33.5,0.5 IC1.H1@52,0.5
NetIC1_L1: IC1.L1 IC2.9 | length 23.2
  Top Layer w0.12: IC2.9@29.33,-2.2 31.8,-2.2 33,-1 IC1.L1@52,-1
NetIC1_M1: IC1.M1 IC2.7 | length 23.4
  Top Layer w0.12: IC2.7@29.33,-2.6 30.2,-2.6 30.5,-2.9 32.1,-2.9 33.5,-1.5 IC1.M1@52,-1.5
NetIC1_P2: IC1.P2 IC4.P2 JMP3.2 pad.1@71.75,-2.75 R102.2 | length 32.5
  Top Layer w0.076: v1(51,-2.25) 52.25,-2.25 IC1.P2@52.5,-2.5
  Top Layer w0.13: IC4.P2@71.5,-2.5 pad.1@71.75,-2.75
  Bottom Layer w0.102: JMP3.2@45.95,-2.2 46.5,-2.2 47.2,-1.5 49.3,-1.5 49.5,-1.7 R102.2@49.5,-2.2 49.55,-2.25 v1(51,-2.25) 51,-3.25 52.65,-4.9 71.2,-4.9 72.1,-4 72.1,-3.1 pad.1@71.75,-2.75
NetIC1_P3: IC1.P3 IC4.P3 JMP2.2 pad.1@72.25,-2.75 R101.1 | length 34.4
  Top Layer w0.076: v1(50.5,-2.75) 51.25,-2.75 52.75,-2.75 IC1.P3@53,-2.5
  Top Layer w0.13: IC4.P3@72,-2.5 pad.1@72.25,-2.75
  Bottom Layer w0.102: JMP2.2@45.95,-4.9 46.2,-4.9 46.55,-5.25 49.5,-5.25 ; v1(50.5,-2.75) 49.55,-3.7 R101.1@49.5,-3.7 49.5,-5.25 ; pad.1@72.25,-2.75 72.4,-2.9 72.4,-4.1 71.25,-5.25 49.5,-5.25
NetIC1_R16: IC1.R16 IC3.L13 pad.1@59.75,-3.25 pad.1@88.4,-4 | length 32.3
  Top Layer w0.13: IC1.R16@59.5,-3 pad.1@59.75,-3.25 ; IC3.L13@88,-4.4 pad.1@88.4,-4
  M1 w0.12: pad.1@59.75,-3.25 60.3,-2.7 62.75,-2.7 64.95,-4.9 78.9,-4.9 80.4,-6.4 86,-6.4 pad.1@88.4,-4
NetIC1_R17: IC1.R17 IC3.L14 pad.1@60.25,-3.25 pad.1@88.4,-4.8 | length 31.5
  Top Layer w0.13: IC1.R17@60,-3 pad.1@60.25,-3.25 ; IC3.L14@88,-5.2 pad.1@88.4,-4.8
  M1 w0.12: pad.1@60.25,-3.25 62.5,-3.25 64.75,-5.5 78.6,-5.5 80.1,-7 86.2,-7 pad.1@88.4,-4.8
NetIC1_T3: IC1.T3 P1.3 R143.2 | length 25.7
  Top Layer w0.076: v1(51.7,-7.05) 51.7,-3.9 51.85,-3.75 52.75,-3.75 IC1.T3@53,-3.5
  Top Layer w0.102: P1.3@63.8,-22.2 v1(63.8,-21.4)
  M1 w0.102: v1(51.7,-7.05) 51.7,-8.95 63.8,-21.05 v1(63.8,-21.4)
  Bottom Layer w0.102: R143.2@63.6,-20.6 63.6,-21.2 v1(63.8,-21.4)
NetIC1_T16: IC1.T16 IC3.K13 pad.1@59.75,-3.75 pad.1@89.2,-4.8 | length 33.1
  Top Layer w0.13: IC1.T16@59.5,-3.5 pad.1@59.75,-3.75 ; IC3.K13@88.8,-4.4 pad.1@89.2,-4.8
  M1 w0.12: pad.1@59.75,-3.75 62.15,-3.75 64.4,-6 78,-6 79.6,-7.6 86.4,-7.6 pad.1@89.2,-4.8
NetIC1_T17: IC1.T17 IC3.J13 pad.1@62.7,-5.75 pad.1@90,-4.8 | length 35
  Top Layer w0.12: IC1.T17@60,-3.5 60.2,-3.7 60.7,-3.7 62.7,-5.7 pad.1@62.7,-5.75
  Top Layer w0.13: IC3.J13@89.6,-4.4 pad.1@90,-4.8
  M1 w0.12: pad.1@62.7,-5.75 62.746,-5.75 63.996,-7 76.9,-7 78.8,-8.9 86.7,-8.9 89.6,-6 89.6,-5.2 pad.1@90,-4.8
NetIC1_U16: IC1.U16 IC3.K14 pad.1@59.75,-4.25 pad.1@89.2,-5.6 | length 33.2
  Top Layer w0.13: IC1.U16@59.5,-4 pad.1@59.75,-4.25 ; IC3.K14@88.8,-5.2 pad.1@89.2,-5.6
  M1 w0.12: pad.1@59.75,-4.25 61.95,-4.25 64.2,-6.5 77.5,-6.5 79.3,-8.3 86.5,-8.3 pad.1@89.2,-5.6
NetIC1_U17: IC1.U17 IC3.J14 pad.1@61.8,-5.8 pad.1@90,-5.6 | length 34.9
  Top Layer w0.12: IC1.U17@60,-4 pad.1@61.8,-5.8
  Top Layer w0.13: IC3.J14@89.6,-5.2 pad.1@90,-5.6
  M1 w0.12: pad.1@61.8,-5.8 63.5,-7.5 76.4,-7.5 78.4,-9.5 86.8,-9.5 90,-6.3 pad.1@90,-5.6
NetIC2_19: IC2.19 IC4.H1 pad.1@30.7,-0.2 pad.1@70.6,0.5 | length 43.7
  Top Layer w0.12: IC2.19@29.33,-0.2 pad.1@30.7,-0.2
  Top Layer w0.13: pad.1@70.6,0.5 IC4.H1@71,0.5
  M2 w0.12: pad.1@30.7,-0.2 49.7,-0.2 51.75,-2.25 59.25,-2.25 60.2,-1.3 68.8,-1.3 pad.1@70.6,0.5
NetIC2_21: IC2.21 IC4.G1 pad.1@32.75,2.25 pad.1@70.6,1 | length 43.9
  Top Layer w0.12: IC2.21@29.33,0.2 30.2,0.2 32.25,2.25 pad.1@32.75,2.25
  Top Layer w0.13: pad.1@70.6,1 IC4.G1@71,1
  M2 w0.12: pad.1@32.75,2.25 36,2.25 37.5,0.75 51.25,0.75 52.25,1.75 69.85,1.75 pad.1@70.6,1
NetIC4_F9: IC4.F9 JMP4.2 pad.1@75.25,1.75 R108.1 | length 3
  Top Layer w0.13: IC4.F9@75,1.5 pad.1@75.25,1.75
  Bottom Layer w0.102: pad.1@75.25,1.75 75.6,2.1 R108.1@75.6,2.75 76.753,2.75 76.8,2.75 77,2.95
NetIC5_4: IC5.4 R126.1 R127.2 | length 1.9
  Top Layer w0.102: IC5.4@81.5,5.7 v1(81.5,6.2)
  Bottom Layer w0.102: R127.2@81.5,5.5 v1(81.5,6.2) R126.1@81.5,6.9
NetIC5_5: IC5.5 R112.1 R113.2 | length 2.7
  Top Layer w0.102: IC5.5@81.5,3.9 81.5,3.3 81.6,3.2 R112.1@81.6,1.2
NetIC6_4: IC6.4 R115.1 R116.2 | length 1.9
  Top Layer w0.2: IC6.4@40.5,4.2 40.7,4 R115.1@41.4,4 R116.2@42.3,4
NetIC7_4: IC7.4 R123.1 R124.2 | length 2.3
  Top Layer w0.102: IC7.4@40.5,-5.5 42.7,-5.5 R124.2@42.8,-5.4
NetP4_1: P4.1 P4.2 R230.2 | length 4.3
  Top Layer w0.203: P4.1@122.8,-5.6 P4.2@124,-5.6 R230.2@127.1,-5.6
NetP8_11: P8.11 P10.12 R210.1 | length 91.7
  Bottom Layer w0.102: R210.1@62.3,-19.4 62.3,-16.7 ; P8.11@65.8,-12 65.8,-9 65.5,-8.7 61.6,-8.7 60.5,-9.8 60.5,-14.9 62.3,-16.7 ; P10.12@109.8,-12 109.8,-9.2 110.3,-8.7 116.4,-8.7 116.9,-9.2 116.9,-14.6 113.2,-18.3 76.5,-18.3 74.9,-16.7 62.3,-16.7
NetP16_1: P16.1 P16.2 R231.2 | length 4.3
  Top Layer w0.203: P16.1@114.8,-5.6 P16.2@116,-5.6 R231.2@119.1,-5.6
NetP17_1: P17.1 P17.2 R232.2 | length 4.3
  Top Layer w0.203: P17.1@106.8,-5.6 P17.2@108,-5.6 R232.2@111.1,-5.6
NetQ1_2: Q1.2 R141.2 | length 1.1
  Top Layer w0.127: Q1.2@48.7,-5 48.8,-5.1 R141.2@49.75,-5.1
NetR222_2: R222.2 R240.1 | length 2
  Bottom Layer w0.203: R240.1@127.1,0.45 R222.2@127.1,2.45
NetR224_2: R224.2 R241.1 | length 2
  Bottom Layer w0.203: R241.1@119.1,0.45 R224.2@119.1,2.45
NetR226_2: R226.2 R242.1 | length 2.1
  Bottom Layer w0.203: R226.2@100.65,0 R242.1@102.7,0
ON0: IC3.A12 P2.5 R233.1 | length 198.1
  Top Layer w0.102: P2.5@23.475,22.2 23.475,21.725 23.8,21.4 27.8,21.4 ; R233.1@27.8,22.3 27.8,21.4 ; IC3.A12@96,-3.6 101.2,-8.8 116.2,-8.8 116.7,-9.3 116.7,-12.1 112.4,-16.4 10.6,-16.4 4,-9.8 4,8.6 13.5,18.1 27.4,18.1 27.8,18.5 27.8,21.4
ON1: IC3.A10 P3.5 R234.1 | length 144.4
  Top Layer w0.102: P3.5@19.875,-22.2 19.875,-21.575 19.7,-21.4 16.7,-21.4 15.9,-22.2 R234.1@13.9,-22.2 13.9,-18.5 15.2,-17.2 112.6,-17.2 117.4,-12.4 117.4,-9.1 116.5,-8.2 102.2,-8.2 IC3.A10@96,-2
ON2: IC3.A6 P14.5 R235.1 | length 66.8
  Top Layer w0.102: IC3.A6@96,1.2 v1(96.4,0.8) ; P14.5@110.425,22.2 110.425,21.775 110.7,21.5 113.8,21.5 114.5,22.2 R235.1@116.7,22.2 v1(116.7,21.3)
  M1 w0.102: v1(96.4,0.8) 102.6,-5.4 121.4,-5.4 123.8,-3 123.8,14.2 v1(116.7,21.3)
ON3: IC3.A8 P15.5 R236.1 | length 58.7
  Top Layer w0.102: IC3.A8@96,-0.4 103.2,-7.6 116.8,-7.6 118.2,-9 118.2,-12.7 112.9,-18 102.8,-18 101,-19.8 R236.1@101,-22.2 102.7,-22.2 103.4,-21.5 106.6,-21.5 106.825,-21.725 P15.5@106.825,-22.2
PG0: IC3.A13 P2.6 R202.1 | length 196.1
  Top Layer w0.102: P2.6@24.675,22.2 25.8,22.2 27.2,23.6 R202.1@27.8,23.6 27.8,24.1 28.1,24.4 30.3,24.4 30.6,24.1 30.6,20.4 27.7,17.5 13.8,17.5 4.6,8.3 4.6,-9.5 11,-15.9 112.4,-15.9 113.3,-15 113.3,-10.1 112.3,-9.1 100.7,-9.1 IC3.A13@96,-4.4
PG1: IC3.A11 P3.6 R204.1 | length 148.3
  Top Layer w0.102: P3.6@18.675,-22.2 16.9,-22.2 15.5,-23.6 R204.1@13.9,-23.6 13.9,-24.2 13.6,-24.5 12.1,-24.5 11.2,-23.6 11.2,-20.5 14.9,-16.8 112.5,-16.8 117.1,-12.2 117.1,-9.3 116.3,-8.5 101.7,-8.5 IC3.A11@96,-2.8
PG2: IC3.A7 P14.6 R206.1 | length 70.1
  Top Layer w0.102: IC3.A7@96,0.4 v1(96.4,0) ; P14.6@111.625,22.2 113.7,22.2 115.1,23.6 R206.1@116.7,23.6 116.7,23.2 117,22.9 121,22.9 v1(124.3,19.6)
  M1 w0.102: v1(96.4,0) 102.4,-6 121.5,-6 124.3,-3.2 v1(124.3,19.6)
PG3: IC3.A9 P15.6 R208.1 | length 62.3
  Top Layer w0.102: IC3.A9@96,-1.2 102.7,-7.9 116.6,-7.9 117.8,-9.1 117.8,-12.5 112.7,-17.6 102.7,-17.6 98.4,-21.9 98.4,-23.8 99,-24.4 100.6,-24.4 101,-24 R208.1@101,-23.5 102,-23.5 103.3,-22.2 P15.6@105.625,-22.2
READY0: IC1.R2 R141.1 | length 3.1
  Top Layer w0.076: R141.1@49.75,-3.9 51.1,-3.9 51.75,-3.25 52.25,-3.25 IC1.R2@52.5,-3
REFCLKN: IC1.K17 IC4.P1 | length 12
  Top Layer w0.12: IC1.K17@60,-0.5 60.25,-0.25 62,-0.25 64.25,-2.5 IC4.P1@71,-2.5
REFCLKP: IC1.K16 IC4.R1 | length 12.5
  Top Layer w0.076: IC1.K16@59.5,-0.5 59.75,-0.75 60.25,-0.75
  Top Layer w0.12: 60.25,-0.75 61.75,-0.75 64,-3 IC4.R1@71,-3
RSTB0: IC3.A1 P5.16 R239.1 | length 143.5
  Top Layer w0.102: v1(19.6,10.9) 19.2,10.9 15.5,14.6 15.5,15.1 17.2,16.8 51,16.8 51.6,16.2 112.9,16.2 113.9,15.2 113.9,9.7 113.3,9.1 99.5,9.1 96,5.6 IC3.A1@96,5.2
  Bottom Layer w0.102: v1(19.6,10.9) v1@19.8,10.9 ; P5.16@19.8,12 v1@19.8,10.9 ; R239.1@27.7,10.6 R239.1@27.6,10.7 27.6,10.1 26.5,9 20,9 19.8,9.2 v1@19.8,10.9
RSTB1: IC3.A2 P7.16 pad.1@68.9,6.9 R238.1 | length 41
  Top Layer w0.102: R238.1@68.9,5.5 pad.1@68.9,6.9 74.4,6.9 76.3,8.8 92.5,8.8 95.6,5.7 95.6,4.8 IC3.A2@96,4.4
  Bottom Layer w0.102: P7.16@63.4,12 63.4,9 65.5,6.9 pad.1@68.9,6.9
RSTB2: IC3.A3 P9.16 R237.1 | length 17.6
  Top Layer w0.102: IC3.A3@96,3.6 97.2,4.8 97.2,5.8 v1(99.9,8.5)
  Bottom Layer w0.102: R237.1@99.9,9.5 v1(99.9,8.5) 106.2,8.5 107,9.3 P9.16@107,12
T_EDIN00N: IC4.U5 P6.22 pad.1@73.25,-4.25 | length 54.1
  Top Layer w0.13: IC4.U5@73,-4 pad.1@73.25,-4.25
  Bottom Layer w0.12: P6.22@25.4,-13.85 25.4,-14.65 26,-15.25 47,-15.25 55.25,-7 68.5,-7
  Bottom Layer w0.13: 68.5,-7 71,-7 73.25,-4.75 pad.1@73.25,-4.25
T_EDIN00P: IC4.T5 P6.21 pad.1@72.75,-3.75 | length 53
  Top Layer w0.13: pad.1@72.75,-3.75 IC4.T5@73,-3.5
  Bottom Layer w0.12: P6.21@25.8,-13.85 25.8,-14.3 26.25,-14.75 46.75,-14.75 55,-6.5 70.85,-6.5 72.75,-4.6 pad.1@72.75,-3.75
T_EDIN02N: IC4.U7 P6.31 pad.1@74.25,-4.25 | length 60.2
  Top Layer w0.13: IC4.U7@74,-4 pad.1@74.25,-4.25
  Bottom Layer w0.12: P6.31@21.8,-13.85 21.8,-15.3 22.75,-16.25 47.5,-16.25 55.75,-8 71.5,-8 74.25,-5.25 pad.1@74.25,-4.25
T_EDIN02P: IC4.T7 P6.30 pad.1@73.75,-3.75 | length 59
  Top Layer w0.13: pad.1@73.75,-3.75 IC4.T7@74,-3.5
  Bottom Layer w0.12: P6.30@22.2,-13.85 22.2,-14.95 23,-15.75 47.25,-15.75 55.5,-7.5 71.2,-7.5 73.75,-4.95 pad.1@73.75,-3.75
T_EDIN10N: IC4.U11 P8.22 pad.1@76.25,-4.25 | length 17.8
  Top Layer w0.13: IC4.U11@76,-4 pad.1@76.25,-4.25
  Bottom Layer w0.12: P8.22@69,-13.85 69,-14.75 69.5,-15.25 73,-15.25 76.25,-12 pad.1@76.25,-4.25
T_EDIN10P: IC4.T11 P8.21 pad.1@75.75,-3.75 | length 16.6
  Top Layer w0.13: pad.1@75.75,-3.75 IC4.T11@76,-3.5
  Bottom Layer w0.12: P8.21@69.4,-13.85 69.4,-14.4 69.75,-14.75 72.75,-14.75 75.75,-11.75 pad.1@75.75,-3.75
T_EDIN12N: IC4.U13 P8.31 pad.1@77.25,-4.25 | length 23.9
  Top Layer w0.13: IC4.U13@77,-4 pad.1@77.25,-4.25
  Bottom Layer w0.12: P8.31@65.4,-13.85 65.4,-15.4 66.25,-16.25 73.5,-16.25 77.25,-12.5 pad.1@77.25,-4.25
T_EDIN12P: IC4.T13 P8.30 pad.1@76.75,-3.75 | length 22.7
  Top Layer w0.13: pad.1@76.75,-3.75 IC4.T13@77,-3.5
  Bottom Layer w0.12: P8.30@65.8,-13.85 65.8,-15.05 66.5,-15.75 73.25,-15.75 76.75,-12.25 pad.1@76.75,-3.75
T_EDIN20N: IC4.P17 P10.22 pad.1@78.75,-2.75 | length 47.2
  Top Layer w0.13: pad.1@78.75,-2.75 IC4.P17@79,-2.5
  Bottom Layer w0.12: pad.1@78.75,-2.75 78.75,-12 83.25,-16.5 111.25,-16.5 112.6,-15.15 P10.22@112.6,-13.85
T_EDIN20P: IC4.P16 P10.21 pad.1@78.25,-2.75 | length 49.3
  Top Layer w0.13: pad.1@78.25,-2.75 IC4.P16@78.5,-2.5
  Bottom Layer w0.12: pad.1@78.25,-2.75 78.25,-12.5 82.75,-17 112,-17 113,-16 P10.21@113,-13.85
T_EDIN22N: IC4.M17 P10.31 pad.1@79.25,-1.25 | length 42.8
  Top Layer w0.13: IC4.M17@79,-1.5 pad.1@79.25,-1.25
  Bottom Layer w0.12: pad.1@79.25,-1.25 79.75,-1.75 79.75,-11 84.25,-15.5 108.5,-15.5 109,-15 P10.31@109,-13.85
T_EDIN22P: IC4.M16 P10.30 pad.1@78.75,-1.75 | length 44.1
  Top Layer w0.13: IC4.M16@78.5,-1.5 pad.1@78.75,-1.75
  Bottom Layer w0.12: pad.1@78.75,-1.75 79.25,-2.25 79.25,-11.5 83.75,-16 108.75,-16 109.4,-15.35 P10.30@109.4,-13.85
T_EDIN30N: IC4.H17 P9.21 pad.1@79.25,0.25 | length 38.1
  Top Layer w0.13: IC4.H17@79,0.5 pad.1@79.25,0.25
  Bottom Layer w0.12: pad.1@79.35,0.25 80,0.9 80,9.5 85.25,14.75 105,14.75 105.4,14.35 P9.21@105.4,13.85
T_EDIN30P: IC4.H16 P9.22 pad.1@78.75,0.75 | length 39.3
  Top Layer w0.13: IC4.H16@78.5,0.5 pad.1@78.75,0.75
  Bottom Layer w0.12: pad.1@78.75,0.75 79.4,1.4 79.4,9.65 85,15.25 105.25,15.25 105.8,14.7 P9.22@105.8,13.85
T_EDIN32N: IC4.F17 P9.30 pad.1@78.75,1.75 | length 42.4
  Top Layer w0.13: pad.1@78.75,1.75 IC4.F17@79,1.5
  Bottom Layer w0.12: pad.1@78.75,1.75 78.75,9.75 84.75,15.75 108,15.75 109,14.75 P9.30@109,13.85
T_EDIN32P: IC4.F16 P9.31 pad.1@78.25,1.75 | length 44.2
  Top Layer w0.13: pad.1@78.25,1.75 IC4.F16@78.5,1.5
  Bottom Layer w0.12: pad.1@78.25,1.75 78.25,10 84.5,16.25 108.5,16.25 109.4,15.35 P9.31@109.4,13.85
T_EDIN40N: IC4.A14 P7.22 pad.1@77.25,4.25 | length 26.9
  Top Layer w0.13: pad.1@77.25,4.25 IC4.A14@77.5,4
  Bottom Layer w0.12: P7.22@62.2,13.85 62.2,14.95 63.75,16.5 73,16.5 74.75,14.75 74.75,9.05 77.25,6.55 pad.1@77.25,4.25
T_EDIN40P: IC4.B14 P7.21 pad.1@77.75,3.75 | length 29.1
  Top Layer w0.13: IC4.B14@77.5,3.5 pad.1@77.75,3.75
  Bottom Layer w0.12: P7.21@61.8,13.85 61.8,15.3 63.5,17 73.25,17 75.25,15 75.25,9.35 77.75,6.85 pad.1@77.75,3.75
T_EDIN42N: IC4.A12 P7.31 pad.1@76.25,4.25 | length 21.1
  Top Layer w0.13: pad.1@76.25,4.25 IC4.A12@76.5,4
  Bottom Layer w0.12: P7.31@65.8,13.85 65.8,14.8 66.5,15.5 72.5,15.5 73.75,14.25 73.75,8.45 76.25,5.95 pad.1@76.25,4.25
T_EDIN42P: IC4.B12 P7.30 pad.1@76.75,3.75 | length 23.3
  Top Layer w0.13: IC4.B12@76.5,3.5 pad.1@76.75,3.75
  Bottom Layer w0.12: P7.30@65.4,13.85 65.4,15.15 66.25,16 72.75,16 74.25,14.5 74.25,8.75 76.75,6.25 pad.1@76.75,3.75
T_EDIN50N: IC4.A10 P5.22 pad.1@75.25,4.25 | length 64.3
  Top Layer w0.13: pad.1@75.25,4.25 IC4.A10@75.5,4
  Bottom Layer w0.12: P5.22@18.6,13.85 18.6,14.8 20.3,16.5 46.4,16.5 55.9,7 63.6,7 64.6,6 74.4,6 75.25,5.15 pad.1@75.25,4.25
T_EDIN50P: IC4.B10 P5.21 pad.1@75.75,3.75 | length 66.5
  Top Layer w0.13: IC4.B10@75.5,3.5 pad.1@75.75,3.75
  Bottom Layer w0.12: P5.21@18.2,13.85 18.2,15.1 20.1,17 46.7,17 56.2,7.5 64,7.5 65,6.5 74.8,6.5 75.75,5.55 pad.1@75.75,3.75
T_EDIN52N: IC4.A8 P5.31 pad.1@74.25,4.25 | length 58.5
  Top Layer w0.13: pad.1@74.25,4.25 IC4.A8@74.5,4
  Bottom Layer w0.12: P5.31@22.2,13.85 22.2,14.8 22.9,15.5 45.2,15.5 54.7,6 62.7,6 63.7,5 73.8,5 74.25,4.55 pad.1@74.25,4.25
T_EDIN52P: IC4.B8 P5.30 pad.1@74.75,3.75 | length 60.6
  Top Layer w0.13: IC4.B8@74.5,3.5 pad.1@74.75,3.75
  Bottom Layer w0.12: P5.30@21.8,13.85 21.8,15.2 22.6,16 45.8,16 55.3,6.5 63.2,6.5 64.2,5.5 74,5.5 74.75,4.75 pad.1@74.75,3.75
Vref: IC1.D2 pad.1@16.2,14.8 R201.2 | length 44.1
  Top Layer w0.076: pad.1@16.2,14.8 19.4,11.6 46.15,11.6 52.75,5 52.75,2.75 IC1.D2@52.5,2.5
  Bottom Layer w0.102: pad.1@16.2,14.8 R201.2@16.2,15.7
pads on no net: IC1.A3 IC1.A4 IC1.A5 IC1.A6 IC1.A7 IC1.A9 IC1.A11 IC1.A13 IC1.B3 IC1.B4 IC1.B5 IC1.B6 IC1.B7 IC1.B9 IC1.B11 IC1.B13 IC1.C2 IC1.C3 IC1.C6 IC1.C7 IC1.C8 IC1.C10 IC1.C12 IC1.C16 IC1.C17 IC1.D6 IC1.D7 IC1.D8 IC1.D10 IC1.D12 IC1.D14 IC1.D15 IC1.D16 IC1.D17 IC1.E2 IC1.E7 IC1.E10 IC1.E11 IC1.E12 IC1.E13 IC1.E14 IC1.E15 IC1.E16 IC1.E17 IC1.F7 IC1.F10 IC1.F11 IC1.F12 IC1.F13 IC1.F14 IC1.F15 IC1.G14 IC1.G15 IC1.G16 IC1.G17 IC1.H4 IC1.H14 IC1.H15 IC1.J4 IC1.J14 IC1.J15 IC1.J16 IC1.J17 IC1.K4 IC1.K14 IC1.K15 IC1.L4 IC1.L5 IC1.L7 IC1.L8 IC1.L9 IC1.L14 IC1.L15 IC1.L16 IC1.L17 IC1.M4 IC1.M5 IC1.M6 IC1.M7 IC1.M8 IC1.M9 IC1.M10 IC1.M14 IC1.M15 IC1.N4 IC1.N5 IC1.N6 IC1.N7 IC1.N8 IC1.N9 IC1.N10 IC1.N11 IC1.N12 IC1.N14 IC1.N15 IC1.N16 IC1.N17 IC1.P1 IC1.P6 IC1.P8 IC1.P10 IC1.P11 IC1.P12 IC1.P15 IC1.R1 IC1.R3 IC1.R6 IC1.R8 IC1.R10 IC1.R11 IC1.R12 IC1.R15 IC1.T1 IC1.T2 IC1.T6 IC1.T8 IC1.T12 IC1.T14 IC1.T15 IC1.U1 IC1.U6 IC1.U8 IC1.U12 IC1.U14 IC1.U15 IC2.2 IC2.4 IC2.20 IC2.22 IC2.23 IC2.25 IC2.26 IC2.27 IC2.28 IC2.29 IC2.31 IC2.33 IC3.A4 IC3.A5 IC3.A14 IC3.B1 IC3.B2 IC3.B3 IC3.B4 IC3.B5 IC3.B6 IC3.B7 IC3.B8 IC3.B9 IC3.B10 IC3.B11 IC3.B12 IC3.B13 IC3.B14 IC3.C1 IC3.C2 IC3.C3 IC3.C4 IC3.C5 IC3.C6 IC3.C7 IC3.C8 IC3.C9 IC3.C10 IC3.C11 IC3.C12 IC3.C13 IC3.C14 IC3.D1 IC3.D2 IC3.D3 IC3.D12 IC3.D13 IC3.D14 IC3.E1 IC3.E2 IC3.E3 IC3.E12 IC3.E13 IC3.E14 IC3.F1 IC3.F2 IC3.F3 IC3.F12 IC3.F13 IC3.F14 IC3.G1 IC3.G2 IC3.G3 IC3.G4 IC3.H1 IC3.H2 IC3.H3 IC3.H4 IC3.J1 IC3.J2 IC3.J3 IC3.J4 IC3.K1 IC3.K2 IC3.K3 IC3.L1 IC3.L2 IC3.L3 IC3.M1 IC3.M2 IC3.M3 IC3.M7 IC3.M8 IC3.M9 IC3.M10 IC3.M11 IC3.M12 IC3.N1 IC3.N2 IC3.N3 IC3.N4 IC3.N5 IC3.N7 IC3.N8 IC3.N9 IC3.N10 IC3.N11 IC3.N12 IC3.N13 IC3.N14 IC3.P1 IC3.P2 IC3.P3 IC3.P5 IC4.A1 IC4.A2 IC4.A3 IC4.A4 IC4.A5 IC4.A6 IC4.A7 IC4.A9 IC4.A11 IC4.A13 IC4.A15 IC4.A16 IC4.A17 IC4.B1 IC4.B2 IC4.B3 IC4.B4 IC4.B5 IC4.B6 IC4.B7 IC4.B9 IC4.B11 IC4.B13 IC4.B15 IC4.B16 IC4.B17 IC4.C1 IC4.C2 IC4.C3 IC4.C4 IC4.C5 IC4.C6 IC4.C7 IC4.C8 IC4.C9 IC4.C10 IC4.C11 IC4.C12 IC4.C13 IC4.C14 IC4.C15 IC4.C16 IC4.C17 IC4.D1 IC4.D2 IC4.D4 IC4.D5 IC4.D6 IC4.D7 IC4.D8 IC4.D9 IC4.D10 IC4.D11 IC4.D12 IC4.D13 IC4.D14 IC4.D15 IC4.D16 IC4.D17 IC4.E2 IC4.E5 IC4.E6 IC4.E7 IC4.E10 IC4.E11 IC4.E12 IC4.E13 IC4.E14 IC4.E15 IC4.E16 IC4.E17 IC4.F5 IC4.F6 IC4.F7 IC4.F10 IC4.F11 IC4.F12 IC4.F13 IC4.F14 IC4.F15 IC4.G14 IC4.G15 IC4.G16 IC4.G17 IC4.H4 IC4.H14 IC4.H15 IC4.J4 IC4.J14 IC4.J15 IC4.J16 IC4.J17 IC4.K4 IC4.K14 IC4.K15 IC4.K16 IC4.K17 IC4.L1 IC4.L4 IC4.L5 IC4.L6 IC4.L7 IC4.L8 IC4.L9 IC4.L14 IC4.L15 IC4.L16 IC4.L17 IC4.M1 IC4.M4 IC4.M5 IC4.M6 IC4.M7 IC4.M8 IC4.M9 IC4.M10 IC4.M11 IC4.M14 IC4.M15 IC4.N4 IC4.N5 IC4.N6 IC4.N7 IC4.N8 IC4.N9 IC4.N10 IC4.N11 IC4.N12 IC4.N13 IC4.N14 IC4.N15 IC4.N16 IC4.N17 IC4.P4 IC4.P5 IC4.P6 IC4.P7 IC4.P8 IC4.P9 IC4.P10 IC4.P11 IC4.P12 IC4.P13 IC4.P14 IC4.P15 IC4.R2 IC4.R3 IC4.R4 IC4.R5 IC4.R6 IC4.R7 IC4.R8 IC4.R9 IC4.R10 IC4.R11 IC4.R12 IC4.R13 IC4.R14 IC4.R15 IC4.R16 IC4.R17 IC4.T1 IC4.T2 IC4.T4 IC4.T6 IC4.T8 IC4.T9 IC4.T10 IC4.T12 IC4.T14 IC4.T15 IC4.T16 IC4.T17 IC4.U1 IC4.U4 IC4.U6 IC4.U8 IC4.U9 IC4.U10 IC4.U12 IC4.U14 IC4.U15 IC4.U16 IC4.U17 IC5.2 IC5.3 IC6.2 IC6.5 IC6.7 IC7.2 IC7.5 IC7.7 JMP1.9 JMP2.9 JMP3.9 JMP4.9 P6.16 P8.16 P10.16
copper on no net: | length 0

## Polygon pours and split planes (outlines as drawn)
GND on plane 1 (split plane): 271 vertices, not listed, extent 0.51,-27.74 129.79,27.74
GND on plane 2 (split plane): 215 vertices, not listed, extent 0.51,-27.74 113.622,27.74
1V2A on plane 2 (split plane): 22.122,14.2 22.128,14.17 22.145,14.145 23.745,12.545 23.77,12.528 23.8,12.522 29.322,12.522 29.322,8.078 11.5,8.078 11.47,8.072 11.445,8.055 11.428,8.03 11.422,8 11.422,-4.8 11.428,-4.83 11.445,-4.855 11.47,-4.872 11.5,-4.878 23.922,-4.878 23.922,-11.622 20.078,-11.622 20.078,-8.4 20.072,-8.37 20.055,-8.345 20.03,-8.328 20,-8.322 4.278,-8.322 4.278,18.068 9.832,23.622 22.122,23.622
1V2B on plane 2 (split plane): 19.922,-11.668 17.245,-14.345 17.228,-14.37 17.222,-14.4 17.222,-15.3 17.228,-15.33 17.245,-15.355 17.845,-15.955 17.87,-15.972 17.9,-15.978 65.4,-15.978 65.43,-15.972 65.455,-15.955 65.472,-15.93 65.478,-15.9 65.478,-12.1 65.472,-12.07 65.455,-12.045 65.43,-12.028 65.4,-12.022 61.078,-12.022 61.078,-9.2 72.8,-9.2 72.8,-19.6 35.422,-19.6 35.393,-19.606 35.367,-19.623 32.068,-22.922 14.732,-22.922 4.278,-12.468 4.278,-8.478 19.922,-8.478
1V5D on plane 2 (split plane): 91.922,-4.322 89.678,-4.322 89.678,-2 89.678,2.8 89.672,2.83 89.655,2.855 89.63,2.872 89.6,2.878 83.832,2.878 82.578,4.132 82.578,5.222 91.922,5.222
1V2D on plane 2 (split plane): 111.122,7 111.128,6.97 111.145,6.945 111.17,6.928 111.2,6.922 129.79,6.922 129.79,-22.74 127.3,-22.74 127.299,-22.74 127.081,-22.749 126.864,-22.778 126.65,-22.825 126.441,-22.891 126.239,-22.975 126.045,-23.076 125.86,-23.194 125.686,-23.327 125.525,-23.475 125.377,-23.636 125.244,-23.81 125.126,-23.995 125.025,-24.189 124.941,-24.391 124.875,-24.6 124.828,-24.814 124.799,-25.031 124.79,-25.249 124.79,-25.25 124.79,-27.74 109.778,-27.74 109.778,-27.5 109.778,-12.7 109.772,-12.67 109.755,-12.645 109.73,-12.628 109.7,-12.622 101.778,-12.622 101.778,5.768 107.732,11.722 111.122,11.722
1V5A on plane 2 (split plane): 95.122,-4.322 92.078,-4.322 92.078,5.3 92.072,5.33 92.055,5.355 92.03,5.372 92,5.378 82.5,5.378 82.47,5.372 82.445,5.355 82.428,5.33 82.422,5.3 82.422,4.1 82.428,4.07 82.445,4.045 83.745,2.745 83.77,2.728 83.8,2.722 89.522,2.722 89.522,-2 89.522,-3.522 86.832,-3.522 86.078,-2.768 86.078,0.5 86.072,0.53 86.055,0.555 86.03,0.572 86,0.578 80.078,0.578 80.078,3.8 80.078,6.922 95.122,6.922
1V2C on plane 2 (split plane): 124.79,25.25 124.79,25.249 124.799,25.031 124.828,24.814 124.875,24.6 124.941,24.391 125.025,24.189 125.126,23.995 125.244,23.81 125.377,23.636 125.525,23.475 125.686,23.327 125.86,23.194 126.045,23.076 126.239,22.975 126.441,22.891 126.65,22.825 126.864,22.778 127.081,22.749 127.299,22.74 127.3,22.74 129.79,22.74 129.79,7.078 111.278,7.078 111.278,11.768 113.755,14.245 113.772,14.27 113.778,14.3 113.778,16 113.772,16.03 113.755,16.055 113.73,16.072 113.7,16.078 80.2,16.078 80.17,16.072 80.145,16.055 72.868,8.778 62.978,8.778 62.978,11.922 67.9,11.922 67.93,11.928 67.955,11.945 70.855,14.845 70.872,14.87 70.878,14.9 70.878,27.74 81.44,27.74 81.44,25.25 81.44,25.249 81.449,25.031 81.478,24.814 81.525,24.6 81.591,24.391 81.675,24.189 81.776,23.995 81.894,23.81 82.027,23.636 82.175,23.475 82.336,23.327 82.51,23.194 82.695,23.076 82.889,22.975 83.091,22.891 83.3,22.825 83.514,22.778 83.731,22.749 83.949,22.74 83.95,22.74 89.95,22.74 89.951,22.74 90.169,22.749 90.386,22.778 90.6,22.825 90.809,22.891 91.011,22.975 91.205,23.076 91.39,23.194 91.564,23.327 91.725,23.475 91.873,23.636 92.006,23.81 92.124,23.995 92.225,24.189 92.309,24.391 92.375,24.6 92.422,24.814 92.451,25.031 92.46,25.249 92.46,25.25 92.46,27.74 124.79,27.74
1V2_RB on plane 3 (split plane): 271 vertices, not listed, extent 0.51,-27.74 129.79,27.74
GND on plane 4 (split plane): 271 vertices, not listed, extent 0.51,-27.74 129.79,27.74

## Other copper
Top Layer:
  rectangle net GND: 6.2,3.5 7.5,4.4
  rectangle net GND: 37.95,-5.1 38.65,-3.9
  rectangle net GND: 38.6,-5.1 39.05,-4.15
  rectangle net GND: 38.1,4.6 39,5.6
  rectangle net GND: 16.3,-21.1 22.6,-17.8
  rectangle net GND: 20.8,-22.6 22.6,-20.6
  rectangle net GND: 14.5,-26.3 29.1,-24.4
  rectangle net 1V2B: 23.2,-22.6 29.7,-17.8
  rectangle net GND: 101.7,-26.4 115.5,-24.5
  rectangle net GND: 103.1,-21.1 109.6,-18.4
  rectangle net 1V2D: 110.1,-22.6 116.7,-18.5
  rectangle net GND: 107.7,-22.6 109.6,-21.1
  rectangle net GND: 107.7,17.9 114.5,21.2
  rectangle net GND: 107.7,21 109.5,22.6
  rectangle net 1V2C: 100.6,17.9 107.1,22.6
  rectangle net GND: 100.7,24.3 116.7,26.3
  rectangle net GND: 56,-26.4 70.4,-24.5
  rectangle net GND: 97.7,1.5 105.7,3.3
  rectangle net GND: 80.2,4.35 81.6,5.25
  rectangle net GND: 22.4,18.8 26.6,20.6
  rectangle net GND: 20.8,18.8 22.6,22.6
  rectangle net GND: 66.4,18.5 70.5,21.2
  rectangle net GND: 64.9,18.5 66.6,22.6
  rectangle net GND: 52,24.2 70.4,26.5
  rectangle net 1V2_RB: 52,20.2 64.3,22.6
  rectangle net BV2: 105.3,-2.95 111.7,-0.95
  rectangle net BV1: 113.3,-2.95 119.7,-0.95
  rectangle net BV0: 121.3,-2.95 127.7,-0.95
  rectangle net 1V2A: 15.5,19.9 20.2,22.6
  rectangle net GND: 15.6,25.6 27.9,27.1
  rectangle net 1V2_RB: 5.4,-7.2 6.6,-5.6
  rectangle net 1V2_RB: 5.7,6.5 7.6,8.3
  rectangle net 1V2T: 7.9,-5.9 9.8,8.1
Bottom Layer:
  rectangle net GND: 26.1,2.1 27.9,3.1
  rectangle net GND: 28.2,2.4 29.9,3.3
  rectangle net GND: 28.1,-3.3 29.4,-2.4
  rectangle net GND: 37.5,-5.1 38.7,-3.9
  rectangle net GND: 37.5,4.6 38.7,5.6
  rectangle net GND: 15.5,9.3 17.9,12.7
  rectangle net GND: 58.7,9.3 61.4,12.6
  rectangle net GND: 63.7,9.3 65.5,12.6
  rectangle net GND: 107.3,9.3 109.1,12.6
  rectangle net GND: 101.7,9.3 105.1,13.425
  rectangle net GND: 101.7,12.425 113.7,13.425
  rectangle net GND: 20.1,9.3 21.9,12.6
  rectangle net GND: 22.1,-12.6 23.9,-11.4
  rectangle net GND: 22.1,-11.5 24.7,-9.3
  rectangle net GND: 110.1,-12.6 111.1,-11.4
  rectangle net GND: 110.1,-11.5 111.9,-9.3
  rectangle net GND: 113.3,-12.7 116.7,-9.3
  rectangle net GND: 67.4,-11.5 68.3,-9.3
  rectangle net GND: 66.1,-12.6 67.5,-9.3
  rectangle net GND: 69.7,-12.7 73.1,-9.3
  rectangle net GND: 26.1,-12.7 29.5,-9.3
  region net GND: 29.5,-12.425 17.5,-12.425 17.5,-13.425 29.5,-13.425
  region net GND: 73.1,-12.425 61.1,-12.425 61.1,-13.425 73.1,-13.425
  region net GND: 116.7,-12.425 104.7,-12.425 104.7,-13.425 116.7,-13.425
  rectangle net GND: 58.7,12.425 70.1,13.425
  rectangle net GND: 15.5,12.425 26.5,13.425
  rectangle net 1V2_RB: 5.6,-7.2 7.5,-5.8
  rectangle net LV_RB: 35.9,-5.1 37.2,-3.9
  rectangle net I_2V5RX: 36.5,-6.4 39.3,-5.3
  rectangle net I_2V5TX: 36.5,3.3 39.3,4.4
  rectangle net LV_RB: 35.7,4.6 37.3,5.8
  rectangle net 1V2T: 25.3,3.4 26.3,4.2
  rectangle net 2V5TX: 29.85,3.6 30.65,4.4
  rectangle net 2V5RX: 28.1,-4.4 28.9,-3.6
  rectangle net 1V2C: 67.7,9.275 69.5,12.275
  rectangle net 1V2C: 65.7,9.275 67.5,12.275
  rectangle net 1V2D: 109.3,9.275 111.1,12.275
  rectangle net 1V2C: 111.3,9.275 113.1,12.275
  region net 1V2D: 109.1,-9.275 107.3,-9.275 107.3,-12.275 109.1,-12.275
  region net 1V2D: 107.1,-9.275 105.3,-9.275 105.3,-12.275 107.1,-12.275
  region net 1V2B: 65.5,-9.275 63.7,-9.275 63.7,-12.275 65.5,-12.275
  region net 1V2B: 63.5,-9.275 61.7,-9.275 61.7,-12.275 63.5,-12.275
  region net 1V2B: 19.9,-9.275 18.1,-9.275 18.1,-12.275 19.9,-12.275
  region net 1V2A: 21.9,-9.275 20.1,-9.275 20.1,-12.275 21.9,-12.275
  rectangle net 1V2A: 22.1,9.275 23.9,12.275
  rectangle net 1V2A: 24.1,9.275 25.9,12.275
plane 2 (plane layer: these items are gaps in the copper):
  lines w0.152: 70.8,28.3 70.8,14.9 67.9,12 62.9,12 62.9,8.7 ; 89.6,-3.6 86.8,-3.6 86,-2.8 86,0.5 80,0.5 80,3.8 80,7 95.2,7 95.2,-4.4 92,-4.4 ; 109.7,-28.3 109.7,-27.5 109.7,-12.7 105.2,-12.7 101.7,-12.7 101.7,5.8 107.7,11.8 111.2,11.8 ; 130.3,7 111.2,7 111.2,11.8 ; 4.2,-8.4 4.2,-12.5 14.7,-23 32.1,-23 35.422,-19.678 72.878,-19.678 72.878,-9.122 61,-9.122 61,-12.1 65.4,-12.1 65.4,-15.9 17.9,-15.9 17.3,-15.3 17.3,-14.4 20,-11.7 ; 4.2,-8.4 20,-8.4 20,-11.7 ; 4.2,-8.4 4.2,18.1 9.8,23.7 22.2,23.7 22.2,14.2 23.8,12.6 29.4,12.6 29.4,8 11.5,8 11.5,-4.8 24,-4.8 24,-11.7 20,-11.7 ; 62.9,8.7 62.9,8.7 ; 62.9,8.7 72.9,8.7 80.2,16 113.7,16 113.7,14.3 111.2,11.8 ; 92,-4.4 89.6,-4.4 89.6,-2 89.6,2.8 83.8,2.8 82.5,4.1 82.5,5.3 92,5.3 92,-4.4

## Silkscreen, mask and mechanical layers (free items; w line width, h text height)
Mechanical 1:
  the board outline again, w0.15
